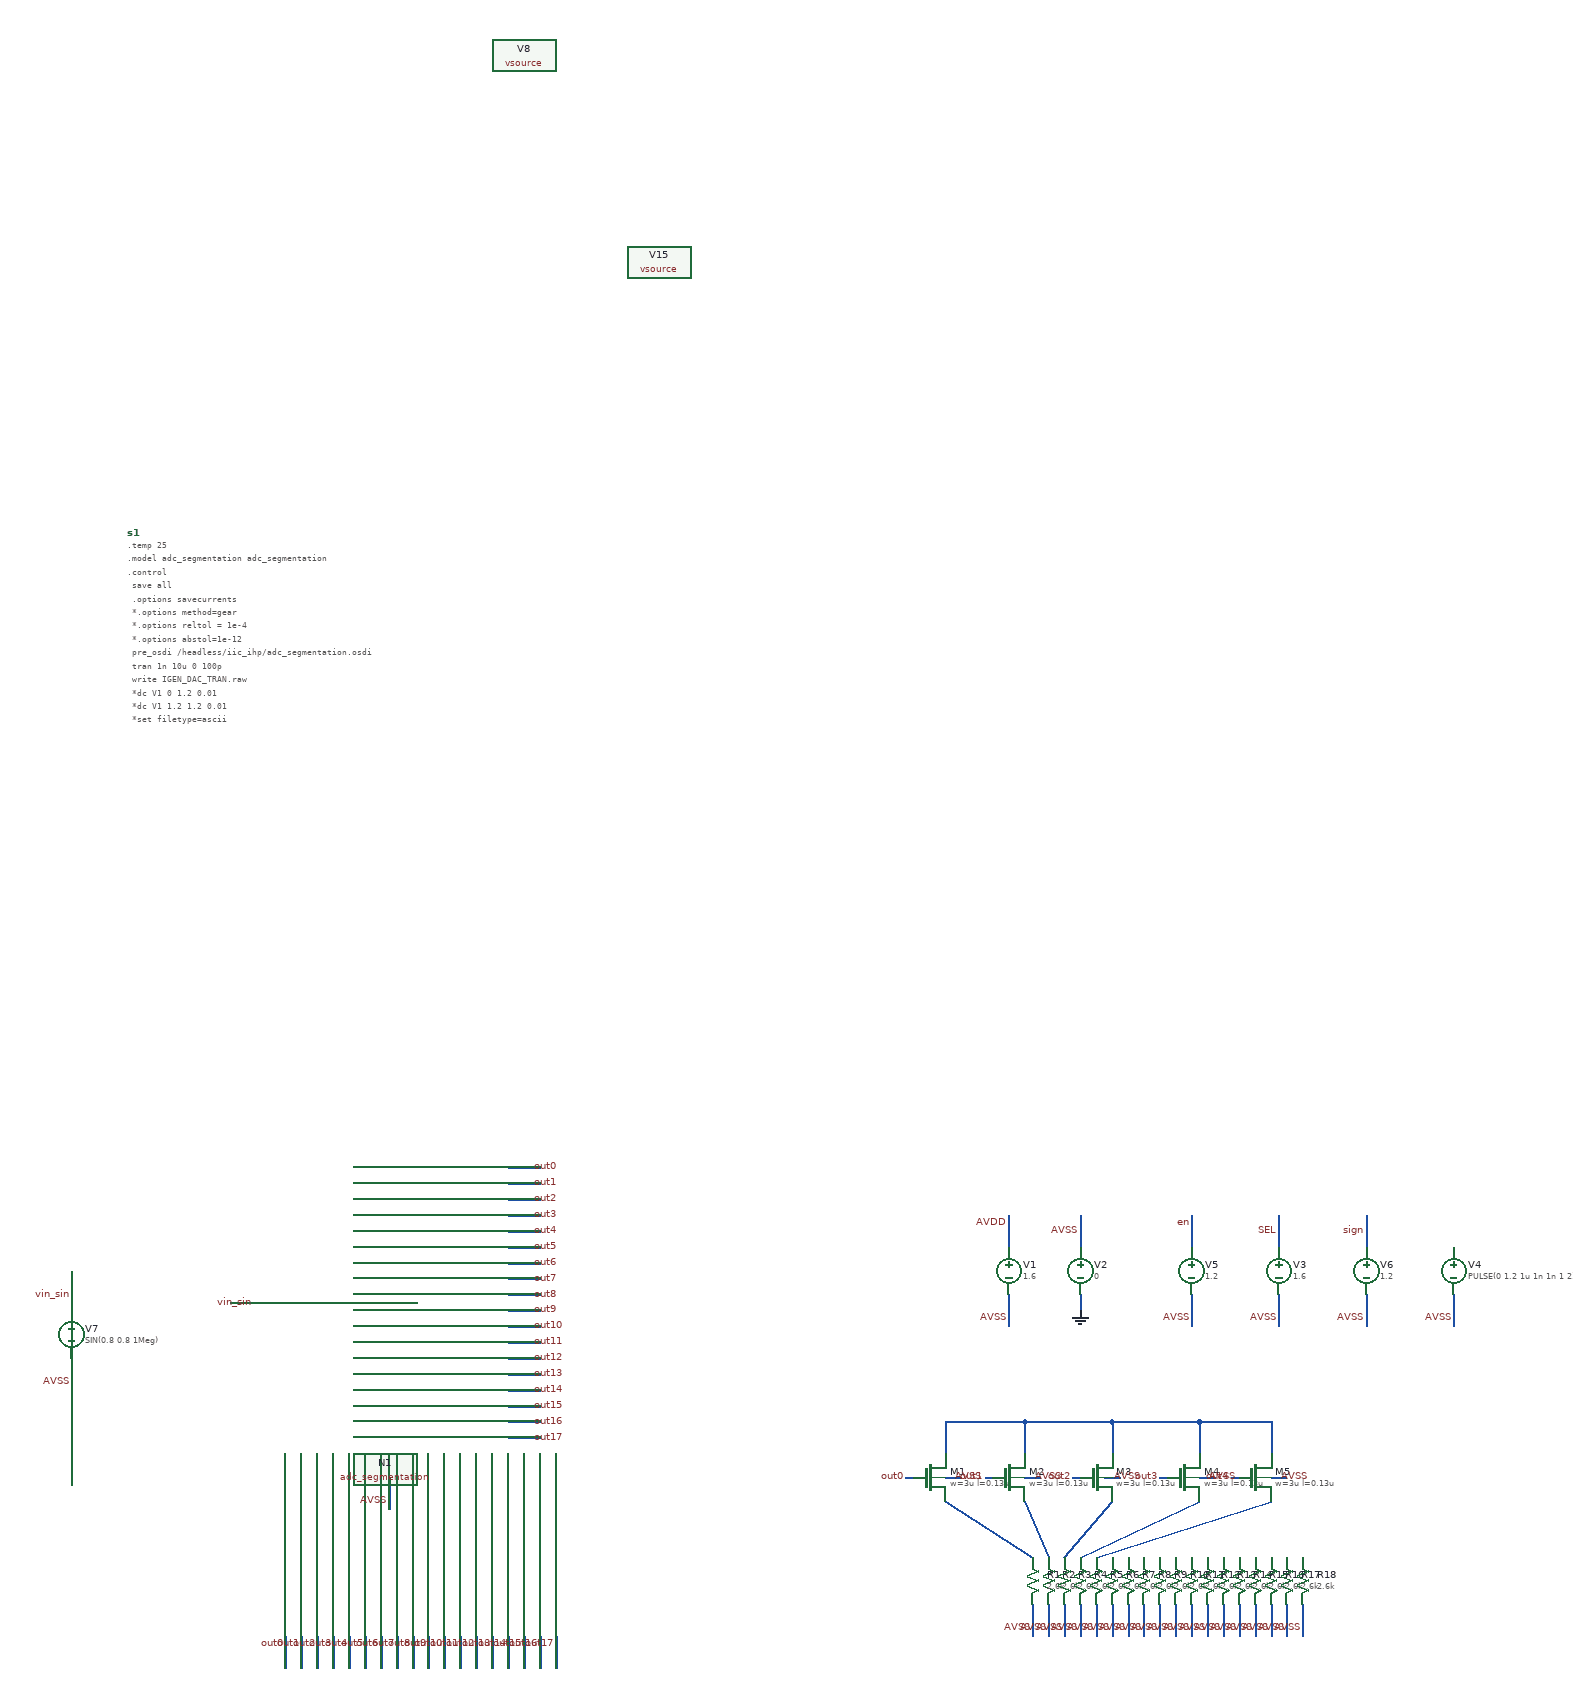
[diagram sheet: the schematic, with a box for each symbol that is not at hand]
v {xschem version=3.4.8RC file_version=1.3}
G {}
K {}
V {}
S {}
F {}
E {}
B 2 1710 -1310 2510 -910 {flags=graph

ypos1=0
ypos2=2
divy=5
subdivy=4
unity=1
divx=5
subdivx=1
unitx=1
logx=0
logy=0
hilight_wave=0
autoload=0
x2=8.4437876e-07
x1=7.0026361e-07
y1=-0.00024832364
y2=0.035780472
rawfile=$netlist_dir/IGEN_DAC_TRAN.raw
dataset=0
color=5
node=vin_sin}
B 2 1710 -1820 2510 -1420 {flags=graph

ypos1=0
ypos2=2
divy=5
subdivy=4
unity=1
divx=5
subdivx=1
unitx=1
logx=0
logy=0
hilight_wave=0
autoload=0
x2=8.4437876e-07
x1=7.0026361e-07
y1=-0.64205456
y2=2.2300224
rawfile=$netlist_dir/IGEN_DAC_TRAN.raw
dataset=0
color=5
node=out0}
B 2 2560 -1820 3360 -1420 {flags=graph

ypos1=0
ypos2=2
divy=5
subdivy=4
unity=1
divx=5
subdivx=1
unitx=1
logx=0
logy=0
hilight_wave=0
autoload=0
x2=8.4437876e-07
x1=7.0026361e-07
y1=-0.64205455
y2=2.2300224
rawfile=$netlist_dir/IGEN_DAC_TRAN.raw
dataset=0
color=5
node=out1}
B 2 3410 -1820 4210 -1420 {flags=graph

ypos1=0
ypos2=2
divy=5
subdivy=4
unity=1
divx=5
subdivx=1
unitx=1
logx=0
logy=0
hilight_wave=0
autoload=0
x2=8.4437876e-07
x1=7.0026361e-07
y1=-0.64205455
y2=2.2300224
rawfile=$netlist_dir/IGEN_DAC_TRAN.raw
dataset=0
color=5
node=out2}
B 2 4280 -1820 5080 -1420 {flags=graph

ypos1=0
ypos2=2
divy=5
subdivy=4
unity=1
divx=5
subdivx=1
unitx=1
logx=0
logy=0
hilight_wave=0
autoload=0
x2=8.4437876e-07
x1=7.0026361e-07
y1=-0.64205455
y2=2.2300224
rawfile=$netlist_dir/IGEN_DAC_TRAN.raw
dataset=0
color=5
node=out3}
N 810 -280 810 -240 {lab=AVSS}
N 960 -670 1000 -670 {lab=out0}
N 960 -650 1000 -650 {lab=out1}
N 960 -630 1000 -630 {lab=out2}
N 960 -610 1000 -610 {lab=out3}
N 960 -590 1000 -590 {lab=out4}
N 960 -570 1000 -570 {lab=out5}
N 960 -550 1000 -550 {lab=out6}
N 960 -530 1000 -530 {lab=out7}
N 960 -510 1000 -510 {lab=out8}
N 960 -490 1000 -490 {lab=out9}
N 960 -470 1000 -470 {lab=out10}
N 960 -450 1000 -450 {lab=out11}
N 960 -430 1000 -430 {lab=out12}
N 960 -410 1000 -410 {lab=out13}
N 960 -390 1000 -390 {lab=out14}
N 960 -370 1000 -370 {lab=out15}
N 960 -350 1000 -350 {lab=out16}
N 960 -330 1000 -330 {lab=out17}
N 610 -500 660 -500 {lab=vin_sin}
N 410 -430 410 -390 {lab=AVSS}
N 410 -540 410 -490 {lab=vin_sin}
N 1590 -610 1590 -570 {lab=AVDD}
N 1590 -510 1590 -470 {lab=AVSS}
N 1680 -510 1680 -490 {lab=GND}
N 1680 -610 1680 -570 {lab=AVSS}
N 1820 -610 1820 -570 {lab=en}
N 1820 -510 1820 -470 {lab=AVSS}
N 2150 -510 2150 -470 {lab=AVSS}
N 1930 -610 1930 -570 {lab=SEL}
N 1930 -510 1930 -470 {lab=AVSS}
N 2040 -610 2040 -570 {lab=sign}
N 2040 -510 2040 -470 {lab=AVSS}
N 680 -80 680 -40 {lab=out0}
N 700 -80 700 -40 {lab=out1}
N 720 -80 720 -40 {lab=out2}
N 740 -80 740 -40 {lab=out3}
N 760 -80 760 -40 {lab=out4}
N 780 -80 780 -40 {lab=out5}
N 800 -80 800 -40 {lab=out6}
N 820 -80 820 -40 {lab=out7}
N 840 -80 840 -40 {lab=out8}
N 860 -80 860 -40 {lab=out9}
N 880 -80 880 -40 {lab=out10}
N 900 -80 900 -40 {lab=out11}
N 920 -80 920 -40 {lab=out12}
N 940 -80 940 -40 {lab=out13}
N 960 -80 960 -40 {lab=out14}
N 980 -80 980 -40 {lab=out15}
N 1000 -80 1000 -40 {lab=out16}
N 1020 -80 1020 -40 {lab=out17}
N 1620 -120 1620 -80 {lab=AVSS}
N 1640 -120 1640 -80 {lab=AVSS}
N 1660 -120 1660 -80 {lab=AVSS}
N 1680 -120 1680 -80 {lab=AVSS}
N 1700 -120 1700 -80 {lab=AVSS}
N 1720 -120 1720 -80 {lab=AVSS}
N 1740 -120 1740 -80 {lab=AVSS}
N 1760 -120 1760 -80 {lab=AVSS}
N 1780 -120 1780 -80 {lab=AVSS}
N 1800 -120 1800 -80 {lab=AVSS}
N 1820 -120 1820 -80 {lab=AVSS}
N 1840 -120 1840 -80 {lab=AVSS}
N 1860 -120 1860 -80 {lab=AVSS}
N 1880 -120 1880 -80 {lab=AVSS}
N 1900 -120 1900 -80 {lab=AVSS}
N 1920 -120 1920 -80 {lab=AVSS}
N 1940 -120 1940 -80 {lab=AVSS}
N 1960 -120 1960 -80 {lab=AVSS}
N 1660 -180 1720 -250 {lab=#net1}
N 1680 -180 1830 -250 {lab=#net2}
N 1700 -180 1920 -250 {lab=#net3}
N 1510 -280 1530 -280 {lab=AVSS}
N 1610 -280 1630 -280 {lab=AVSS}
N 1710 -280 1730 -280 {lab=AVSS}
N 1830 -280 1850 -280 {lab=AVSS}
N 1920 -280 1940 -280 {lab=AVSS}
N 1510 -250 1620 -180 {lab=#net4}
N 1610 -250 1640 -180 {lab=#net5}
N 1510 -350 1510 -310 {lab=#net6}
N 1830 -350 1920 -350 {lab=#net6}
N 1920 -350 1920 -310 {lab=#net6}
N 1830 -350 1830 -310 {lab=#net6}
N 1720 -350 1830 -350 {lab=#net6}
N 1720 -350 1720 -310 {lab=#net6}
N 1610 -350 1720 -350 {lab=#net6}
N 1610 -350 1610 -310 {lab=#net6}
N 1510 -350 1610 -350 {lab=#net6}
N 1460 -280 1470 -280 {lab=out0}
N 1560 -280 1570 -280 {lab=out1}
N 1670 -280 1680 -280 {lab=out2}
N 1780 -280 1790 -280 {lab=out3}
N 1870 -280 1880 -280 {lab=out4}
C {adc_segmentation.sym} 810 -500 0 0 {name=N1 model=adc_segmentation}
C {lab_wire.sym} 810 -250 0 0 {name=p60 sig_type=std_logic lab=AVSS}
C {lab_wire.sym} 990 -670 0 1 {name=p69 sig_type=std_logic lab=out0}
C {lab_wire.sym} 990 -650 0 1 {name=p70 sig_type=std_logic lab=out1}
C {lab_wire.sym} 990 -630 0 1 {name=p73 sig_type=std_logic lab=out2}
C {lab_wire.sym} 990 -610 0 1 {name=p74 sig_type=std_logic lab=out3}
C {lab_wire.sym} 990 -590 0 1 {name=p75 sig_type=std_logic lab=out4}
C {lab_wire.sym} 990 -570 0 1 {name=p76 sig_type=std_logic lab=out5}
C {lab_wire.sym} 990 -550 0 1 {name=p77 sig_type=std_logic lab=out6}
C {lab_wire.sym} 990 -530 0 1 {name=p78 sig_type=std_logic lab=out7}
C {lab_wire.sym} 990 -510 0 1 {name=p79 sig_type=std_logic lab=out8}
C {lab_wire.sym} 990 -490 0 1 {name=p80 sig_type=std_logic lab=out9}
C {lab_wire.sym} 990 -470 0 1 {name=p81 sig_type=std_logic lab=out10}
C {lab_wire.sym} 990 -450 0 1 {name=p82 sig_type=std_logic lab=out11}
C {lab_wire.sym} 990 -430 0 1 {name=p83 sig_type=std_logic lab=out12}
C {lab_wire.sym} 990 -410 0 1 {name=p84 sig_type=std_logic lab=out13}
C {lab_wire.sym} 990 -390 0 1 {name=p85 sig_type=std_logic lab=out14}
C {lab_wire.sym} 990 -370 0 1 {name=p86 sig_type=std_logic lab=out15}
C {lab_wire.sym} 990 -350 0 1 {name=p87 sig_type=std_logic lab=out16}
C {lab_wire.sym} 990 -330 0 1 {name=p88 sig_type=std_logic lab=out17}
C {lab_wire.sym} 640 -500 0 0 {name=p89 sig_type=std_logic lab=vin_sin}
C {vsource.sym} 410 -460 0 0 {name=V7 value="SIN(0.8 0.8 1Meg)"  savecurrent=false}
C {lab_wire.sym} 410 -400 0 0 {name=p90 sig_type=std_logic lab=AVSS}
C {lab_wire.sym} 410 -510 1 0 {name=p91 sig_type=std_logic lab=vin_sin}
C {code_shown.sym} 480 -1470 0 0 {name=s1 only_toplevel=false value="
.temp 25
.model adc_segmentation adc_segmentation
.control
 save all
 .options savecurrents
 *.options method=gear
 *.options reltol = 1e-4
 *.options abstol=1e-12
 pre_osdi /headless/iic_ihp/adc_segmentation.osdi
 tran 1n 10u 0 100p
 write IGEN_DAC_TRAN.raw 
 *dc V1 0 1.2 0.01
 *dc V1 1.2 1.2 0.01
 *set filetype=ascii
 *write IGEN_DAC_DC.raw
 *plot v(VBIAS)
 *plot i(V7)
 *plot i(V8)
 *plot i(V9)
 *plot @i0[current]
.endc
.include /foss/pdks/ihp-sg13g2/libs.ref/sg13g2_stdcell/spice/sg13g2_stdcell.spice
.lib /foss/pdks/ihp-sg13g2/libs.tech/ngspice/models/cornerMOSlv.lib mos_tt
.lib /foss/pdks/ihp-sg13g2/libs.tech/ngspice/models/cornerCAP.lib cap_typ
.lib /foss/pdks/ihp-sg13g2/libs.tech/ngspice/models/cornerRES.lib res_typ
"}
C {vsource.sym} 1590 -540 0 0 {name=V1 value=1.6 savecurrent=false}
C {lab_wire.sym} 1590 -480 0 0 {name=p40 sig_type=std_logic lab=AVSS}
C {gnd.sym} 1680 -490 0 0 {name=l1 lab=GND}
C {vsource.sym} 1680 -540 0 0 {name=V2 value=0 savecurrent=false}
C {lab_wire.sym} 1680 -590 0 0 {name=p41 sig_type=std_logic lab=AVSS}
C {vsource.sym} 1930 -540 0 0 {name=V3 value=1.6 savecurrent=false}
C {lab_wire.sym} 1820 -600 0 0 {name=p42 sig_type=std_logic lab=en}
C {lab_wire.sym} 1820 -480 0 0 {name=p43 sig_type=std_logic lab=AVSS}
C {vsource.sym} 2150 -540 0 0 {name=V4 value="PULSE(0 1.2 1u 1n 1n 1 2)"  savecurrent=false}
C {lab_wire.sym} 2150 -480 0 0 {name=p47 sig_type=std_logic lab=AVSS}
C {vsource.sym} 1820 -540 0 0 {name=V5 value=1.2 savecurrent=false}
C {lab_wire.sym} 1930 -480 0 0 {name=p48 sig_type=std_logic lab=AVSS}
C {lab_wire.sym} 1930 -590 0 0 {name=p5 sig_type=std_logic lab=SEL}
C {vsource.sym} 2040 -540 0 0 {name=V6 value=1.2 savecurrent=false}
C {lab_wire.sym} 2040 -480 0 0 {name=p55 sig_type=std_logic lab=AVSS}
C {lab_wire.sym} 2040 -590 0 0 {name=p56 sig_type=std_logic lab=sign}
C {lab_wire.sym} 1590 -600 0 0 {name=p39 sig_type=std_logic lab=AVDD}
C {res.sym} 1640 -150 0 0 {name=R2
value=2.6k
footprint=1206
device=resistor
m=1}
C {lab_wire.sym} 680 -70 3 1 {name=p1 sig_type=std_logic lab=out0}
C {lab_wire.sym} 700 -70 3 1 {name=p2 sig_type=std_logic lab=out1}
C {lab_wire.sym} 720 -70 3 1 {name=p3 sig_type=std_logic lab=out2}
C {lab_wire.sym} 740 -70 3 1 {name=p4 sig_type=std_logic lab=out3}
C {lab_wire.sym} 760 -70 3 1 {name=p6 sig_type=std_logic lab=out4}
C {lab_wire.sym} 780 -70 3 1 {name=p7 sig_type=std_logic lab=out5}
C {lab_wire.sym} 800 -70 3 1 {name=p8 sig_type=std_logic lab=out6}
C {lab_wire.sym} 820 -70 3 1 {name=p9 sig_type=std_logic lab=out7}
C {lab_wire.sym} 840 -70 3 1 {name=p10 sig_type=std_logic lab=out8}
C {lab_wire.sym} 860 -70 3 1 {name=p11 sig_type=std_logic lab=out9}
C {lab_wire.sym} 880 -70 3 1 {name=p12 sig_type=std_logic lab=out10}
C {lab_wire.sym} 900 -70 3 1 {name=p13 sig_type=std_logic lab=out11}
C {lab_wire.sym} 920 -70 3 1 {name=p14 sig_type=std_logic lab=out12}
C {lab_wire.sym} 940 -70 3 1 {name=p15 sig_type=std_logic lab=out13}
C {lab_wire.sym} 960 -70 3 1 {name=p16 sig_type=std_logic lab=out14}
C {lab_wire.sym} 980 -70 3 1 {name=p17 sig_type=std_logic lab=out15}
C {lab_wire.sym} 1000 -70 3 1 {name=p18 sig_type=std_logic lab=out16}
C {lab_wire.sym} 1020 -70 3 1 {name=p19 sig_type=std_logic lab=out17}
C {res.sym} 1620 -150 0 0 {name=R1
value=2.6k
footprint=1206
device=resistor
m=1}
C {res.sym} 1660 -150 0 0 {name=R3
value=2.6k
footprint=1206
device=resistor
m=1}
C {res.sym} 1680 -150 0 0 {name=R4
value=2.6k
footprint=1206
device=resistor
m=1}
C {res.sym} 1700 -150 0 0 {name=R5
value=2.6k
footprint=1206
device=resistor
m=1}
C {res.sym} 1720 -150 0 0 {name=R6
value=2.6k
footprint=1206
device=resistor
m=1}
C {res.sym} 1740 -150 0 0 {name=R7
value=2.6k
footprint=1206
device=resistor
m=1}
C {res.sym} 1760 -150 0 0 {name=R8
value=2.6k
footprint=1206
device=resistor
m=1}
C {res.sym} 1780 -150 0 0 {name=R9
value=2.6k
footprint=1206
device=resistor
m=1}
C {res.sym} 1800 -150 0 0 {name=R10
value=2.6k
footprint=1206
device=resistor
m=1}
C {res.sym} 1820 -150 0 0 {name=R11
value=2.6k
footprint=1206
device=resistor
m=1}
C {res.sym} 1840 -150 0 0 {name=R12
value=2.6k
footprint=1206
device=resistor
m=1}
C {res.sym} 1860 -150 0 0 {name=R13
value=2.6k
footprint=1206
device=resistor
m=1}
C {res.sym} 1880 -150 0 0 {name=R14
value=2.6k
footprint=1206
device=resistor
m=1}
C {res.sym} 1900 -150 0 0 {name=R15
value=2.6k
footprint=1206
device=resistor
m=1}
C {res.sym} 1920 -150 0 0 {name=R16
value=2.6k
footprint=1206
device=resistor
m=1}
C {res.sym} 1940 -150 0 0 {name=R17
value=2.6k
footprint=1206
device=resistor
m=1}
C {res.sym} 1960 -150 0 0 {name=R18
value=2.6k
footprint=1206
device=resistor
m=1}
C {lab_wire.sym} 1620 -90 0 0 {name=p20 sig_type=std_logic lab=AVSS}
C {lab_wire.sym} 1640 -90 0 0 {name=p21 sig_type=std_logic lab=AVSS}
C {lab_wire.sym} 1660 -90 0 0 {name=p22 sig_type=std_logic lab=AVSS}
C {lab_wire.sym} 1680 -90 0 0 {name=p23 sig_type=std_logic lab=AVSS}
C {lab_wire.sym} 1700 -90 0 0 {name=p24 sig_type=std_logic lab=AVSS}
C {lab_wire.sym} 1720 -90 0 0 {name=p25 sig_type=std_logic lab=AVSS}
C {lab_wire.sym} 1740 -90 0 0 {name=p26 sig_type=std_logic lab=AVSS}
C {lab_wire.sym} 1760 -90 0 0 {name=p27 sig_type=std_logic lab=AVSS}
C {lab_wire.sym} 1780 -90 0 0 {name=p28 sig_type=std_logic lab=AVSS}
C {lab_wire.sym} 1800 -90 0 0 {name=p29 sig_type=std_logic lab=AVSS}
C {lab_wire.sym} 1820 -90 0 0 {name=p30 sig_type=std_logic lab=AVSS}
C {lab_wire.sym} 1840 -90 0 0 {name=p31 sig_type=std_logic lab=AVSS}
C {lab_wire.sym} 1860 -90 0 0 {name=p32 sig_type=std_logic lab=AVSS}
C {lab_wire.sym} 1880 -90 0 0 {name=p33 sig_type=std_logic lab=AVSS}
C {lab_wire.sym} 1900 -90 0 0 {name=p34 sig_type=std_logic lab=AVSS}
C {lab_wire.sym} 1920 -90 0 0 {name=p35 sig_type=std_logic lab=AVSS}
C {lab_wire.sym} 1940 -90 0 0 {name=p36 sig_type=std_logic lab=AVSS}
C {lab_wire.sym} 1960 -90 0 0 {name=p37 sig_type=std_logic lab=AVSS}
C {sg13g2_pr/sg13_lv_nmos.sym} 1490 -280 0 0 {name=M1
l=0.13u
w=3u
ng=1
m=1
model=sg13_lv_nmos
spiceprefix=X
}
C {sg13g2_pr/sg13_lv_nmos.sym} 1590 -280 0 0 {name=M2
l=0.13u
w=3u
ng=1
m=1
model=sg13_lv_nmos
spiceprefix=X
}
C {sg13g2_pr/sg13_lv_nmos.sym} 1700 -280 0 0 {name=M3
l=0.13u
w=3u
ng=1
m=1
model=sg13_lv_nmos
spiceprefix=X
}
C {sg13g2_pr/sg13_lv_nmos.sym} 1810 -280 0 0 {name=M4
l=0.13u
w=3u
ng=1
m=1
model=sg13_lv_nmos
spiceprefix=X
}
C {sg13g2_pr/sg13_lv_nmos.sym} 1900 -280 0 0 {name=M5
l=0.13u
w=3u
ng=1
m=1
model=sg13_lv_nmos
spiceprefix=X
}
C {lab_wire.sym} 1520 -280 0 1 {name=p38 sig_type=std_logic lab=AVSS}
C {lab_wire.sym} 1620 -280 0 1 {name=p44 sig_type=std_logic lab=AVSS}
C {lab_wire.sym} 1720 -280 0 1 {name=p45 sig_type=std_logic lab=AVSS}
C {lab_wire.sym} 1840 -280 0 1 {name=p46 sig_type=std_logic lab=AVSS}
C {lab_wire.sym} 1930 -280 0 1 {name=p49 sig_type=std_logic lab=AVSS}
C {lab_wire.sym} 1460 -280 0 0 {name=p50 sig_type=std_logic lab=out0}
C {lab_wire.sym} 1560 -280 0 0 {name=p51 sig_type=std_logic lab=out1}
C {lab_wire.sym} 1670 -280 0 0 {name=p52 sig_type=std_logic lab=out2}
C {lab_wire.sym} 1780 -280 0 0 {name=p53 sig_type=std_logic lab=out3}
C {lab_wire.sym} 1870 -280 0 0 {name=p54 sig_type=std_logic lab=out4}
C {vsource.sym} 980 -2070 0 0 {name=V8 value="PULSE(0 1.6 0 10u 10u 0 20u)"  savecurrent=false}
C {vsource.sym} 1150 -1810 0 0 {name=V15 value="SIN(0.8 0.8 10k)"  savecurrent=false}
